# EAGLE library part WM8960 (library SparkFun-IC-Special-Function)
Cirrus Logic WM890 - Stereo Audio CODEC I2S enabled audio CODEC with stereo microphone input ADC's and stereo audio output DAC's. Onboard 1W Class D Speaker driver is also capable of driving an 8 Ohm speaker. Also has an onboard headphone driver.

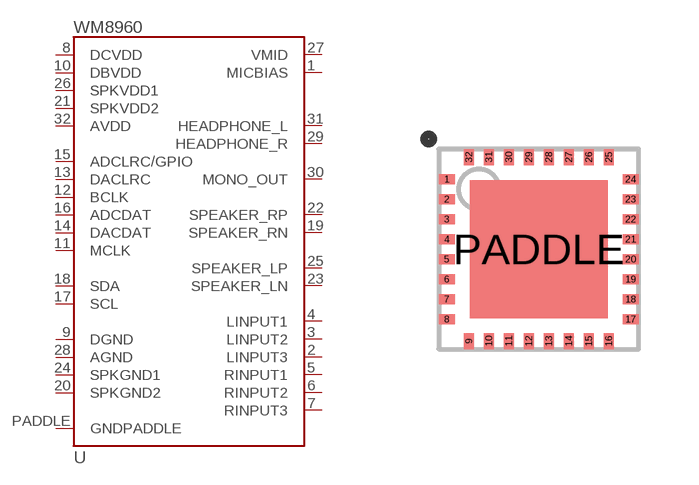
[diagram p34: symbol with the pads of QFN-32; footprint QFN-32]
Designator prefix U

## WM8960 (PROD_ID: IC-14824; VALUE: WM8960)  [QFN-32]
1  MICBIAS
2  LINPUT3
3  LINPUT2
4  LINPUT1
5  RINPUT1
6  RINPUT2
7  RINPUT3
8  DCVDD
9  DGND
10  DBVDD
11  MCLK
12  BCLK
13  DACLRC
14  DACDAT
15  ADCLRC/GPIO
16  ADCDAT
17  SCL
18  SDA
19  SPEAKER_RN
20  SPKGND2
21  SPKVDD2
22  SPEAKER_RP
23  SPEAKER_LN
24  SPKGND1
25  SPEAKER_LP
26  SPKVDD1
27  VMID
28  AGND
29  HEADPHONE_R
30  MONO_OUT
31  HEADPHONE_L
32  AVDD
PADDLE  GNDPADDLE

## Footprint QFN-32 (pad centres in mm)
QFN-32 - Used for WM8960 Audio Codec Specifications: Pin count: 32 Pin pitch: 0.5mm Area: 5mm x 5mm Datasheet referenced for footprint
smd 0.4 x 0.25: 1 -2.3,1.75; 2 -2.3,1.25; 3 -2.3,0.75; 4 -2.3,0.25; 5 -2.3,-0.25; 6 -2.3,-0.75; 7 -2.3,-1.25; 8 -2.3,-1.75; 17 2.3,-1.75; 18 2.3,-1.25; 19 2.3,-0.75; 20 2.3,-0.25; 21 2.3,0.25; 22 2.3,0.75; 23 2.3,1.25; 24 2.3,1.75
smd 0.25 x 0.4: 9 -1.75,-2.3; 10 -1.25,-2.3; 11 -0.75,-2.3; 12 -0.25,-2.3; 13 0.25,-2.3; 14 0.75,-2.3; 15 1.25,-2.3; 16 1.75,-2.3; 25 1.75,2.3; 26 1.25,2.3; 27 0.75,2.3; 28 0.25,2.3; 29 -0.25,2.3; 30 -0.75,2.3; 31 -1.25,2.3; 32 -1.75,2.3
smd 3.45 x 3.45: PADDLE 0,0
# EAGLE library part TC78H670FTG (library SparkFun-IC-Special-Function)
Toshiba TC78H670FTG Stepper Motor Driver Clock-in and Serial controlled Bipolar Stepping Motor Driver Datasheet SparkFun Products: SparkFun ProDriver - Stepper Motor Driver (TC78H670FTG)

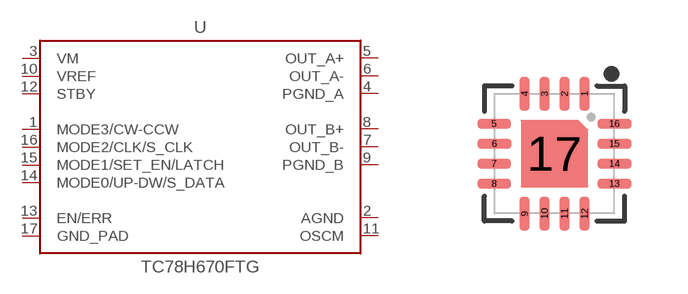
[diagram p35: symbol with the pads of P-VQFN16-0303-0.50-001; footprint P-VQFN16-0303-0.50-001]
Designator prefix -

## TC78H670FTG (PROD_ID: IC-15170; VALUE: TC78H670FTG)  [P-VQFN16-0303-0.50-001]
1  MODE3/CW-CCW
2  AGND
3  VM
4  PGND_A
5  OUT_A+
6  OUT_A-
7  OUT_B-
8  OUT_B+
9  PGND_B
10  VREF
11  OSCM
12  STBY
13  EN/ERR
14  MODE0/UP-DW/S_DATA
15  MODE1/SET_EN/LATCH
16  MODE2/CLK/S_CLK
17  GND_PAD

## Footprint P-VQFN16-0303-0.50-001 (pad centres in mm)
QFN-16 - 3.0mm x 3.0mm package for the MLX90393 Specifications: Pin count: 16 Pin pitch: .5mm Area: 3.0mm x 3.0mm Datasheet referenced for footprint
smd 0.255 x 0.85: 1 0.75,1.498; 2 0.25,1.498; 3 -0.25,1.498; 4 -0.75,1.498; 9 -0.75,-1.506; 10 -0.25,-1.506; 11 0.25,-1.506; 12 0.75,-1.506
smd 0.85 x 0.255: 5 -1.508,0.75; 6 -1.5,0.25; 7 -1.508,-0.25; 8 -1.508,-0.75; 13 1.496,-0.75; 14 1.496,-0.25; 15 1.496,0.25; 16 1.496,0.75
smd 1.3 x 1.3: 17 0,0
